! (c) 2009  Infineon Technologies AG, Munich
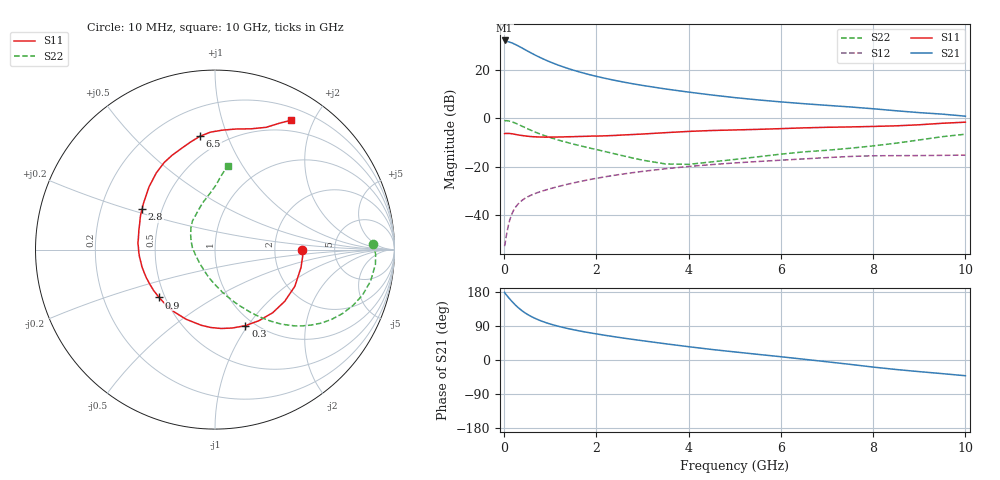
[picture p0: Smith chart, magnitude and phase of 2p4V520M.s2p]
! Infineon Technologies  Discrete & RF Semiconductors
! BFP420
! VCE =  4.5 V,  IC =  20 mA
! Common Emitter S-Parameters:  Nov 2009
# GHz  S  MA  R  50
!  f  S11  S21  S12  S22
! GHz  MAG  ANG  MAG  ANG  MAG  ANG  MAG  ANG
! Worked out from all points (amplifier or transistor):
!   46 points, 10 MHz to 10 GHz, reference 50 ohm
!   highest |S21| = 32.2 dB at 10 MHz (marker M1)
!   |S21| within 3 dB of that: start of sweep to 377.4 MHz
!   unconditionally stable (mu >= 1): start of sweep to 30.36 MHz; 1.831 GHz to end of sweep
!   at 300 MHz: K = 0.42, MSG = 32.7 dB, |S12| = -35.4 dB
!   at 1.7 GHz: K = 0.97, MSG = 22.3 dB, |S12| = -25.8 dB
!   at 10 GHz: K = 1.07, MAG = 6.4 dB, |S12| = -15.2 dB
!   lowest NFmin = 1.23 dB at 900 MHz
!   S11 on the Smith chart (normalised r, x): 10 MHz: 2.87, -0.03; 300 MHz: 0.91, -0.97; 900 MHz: 0.46, -0.30; 2.8 GHz: 0.39, +0.22; 6.5 GHz: 0.38, +0.80; 10 GHz: 0.35, +1.69
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0.01  0.4829 -0.5  40.64 178.4  0.0023 29.2  0.8808 2.2
0.02  0.4901 -4.1  39.32 176.0  0.0026 29.8  0.8954 -1.6
0.1  0.4896 -24.7  38.01 164.2  0.0068 62.6  0.8847 -11.4
0.15  0.4837 -36.5  36.67 157.1  0.0097 64.5  0.8602 -17.1
0.2  0.4765 -47.6  35.11 150.6  0.0124 63.7  0.8286 -22.2
0.25  0.4655 -58.4  33.27 144.3  0.0148 62.3  0.7933 -26.8
0.3  0.4563 -68.2  31.53 138.7  0.017 60.9  0.7555 -31.1
0.35  0.4476 -77.3  29.74 133.6  0.0189 59.4  0.7183 -34.8
0.45  0.4346 -93.2  26.34 124.6  0.0223 56.9  0.6477 -41.0
0.6  0.4201 -112.5  22.02 113.9  0.0264 54.6  0.5579 -48.2
0.7  0.4151 -123.0  19.67 108.2  0.0288 53.8  0.509 -51.8
0.9  0.4101 -139.5  16.02 98.8  0.0332 53.0  0.4326 -57.8
1.2  0.4135 -157.6  12.32 88.2  0.0398 52.7  0.3513 -65.2
1.7  0.4252 -178.4  8.735 75.2  0.051 51.6  0.2647 -76.1
2.2  0.437 166.2  6.679 64.9  0.0625 49.3  0.2053 -87.3
2.8  0.4647 151.1  5.162 54.2  0.076 45.2  0.1511 -105.8
3.5  0.5074 136.4  4.049 42.8  0.0912 39.6  0.1146 -137.6
5.5  0.5934 108.5  2.41 14.9  0.1287 22.2  0.1609 147.6
6.5  0.6373 97.5  2.01 2.0  0.1458 13.4  0.2037 128.0
7  0.6548 92.2  1.858 -4.7  0.155 8.8  0.2197 119.4
8.5  0.7022 73.4  1.436 -25.1  0.1701 -7.9  0.3078 96.2
10  0.8352 59.6  1.111 -41.5  0.1746 -19.1  0.4715 81.5
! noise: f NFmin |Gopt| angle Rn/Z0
0.9  1.23  0.16  -154  0.13
1.8  1.51  0.24  -144  0.13
2.4  1.66  0.22  -141  0.15
3  1.69  0.3  -132  0.16
4  1.82  0.42  -115  0.23
5  2.28  0.48  -96  0.37
6  2.65  0.52  -86  0.56
